VERSION 5.7 ;
  NOWIREEXTENSIONATPIN ON ;
  DIVIDERCHAR "/" ;
  BUSBITCHARS "[]" ;
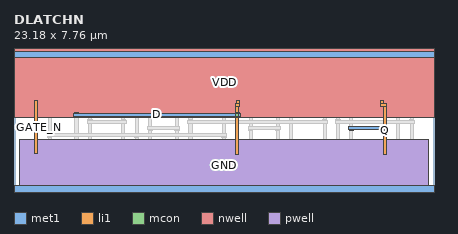
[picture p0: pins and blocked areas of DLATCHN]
MACRO DLATCHN
  CLASS CORE ;
  FOREIGN DLATCHN ;
  ORIGIN 0.000 0.000 ;
  SIZE 23.180 BY 7.760 ;
  SYMMETRY X Y ;
  SITE unitrh ;
  PIN Q
    DIRECTION OUTPUT ;
    USE SIGNAL ;
    ANTENNAGATEAREA 1.027250 ;
    ANTENNADIFFAREA 0.963050 ;
    PORT
      LAYER met1 ;
        RECT 18.505 3.595 18.735 3.625 ;
        RECT 20.355 3.595 20.585 3.625 ;
        RECT 18.475 3.425 20.615 3.595 ;
        RECT 18.505 3.395 18.735 3.425 ;
        RECT 20.355 3.395 20.585 3.425 ;
    END
    PORT
      LAYER li1 ;
        RECT 20.230 4.890 20.400 5.050 ;
        RECT 20.230 4.720 20.555 4.890 ;
        RECT 20.385 2.095 20.555 4.720 ;
      LAYER mcon ;
        RECT 20.385 3.425 20.555 3.595 ;
    END
  END Q
  PIN D
    DIRECTION INPUT ;
    USE SIGNAL ;
    ANTENNAGATEAREA 2.054500 ;
    PORT
      LAYER met1 ;
        RECT 3.335 4.335 3.565 4.365 ;
        RECT 12.215 4.335 12.445 4.365 ;
        RECT 3.305 4.165 12.475 4.335 ;
        RECT 3.335 4.135 3.565 4.165 ;
        RECT 12.215 4.135 12.445 4.165 ;
    END
    PORT
      LAYER li1 ;
        RECT 12.275 4.890 12.445 5.045 ;
        RECT 12.245 4.715 12.445 4.890 ;
        RECT 12.245 2.095 12.415 4.715 ;
      LAYER mcon ;
        RECT 12.245 4.165 12.415 4.335 ;
    END
  END D
  PIN GATE_N
    DIRECTION INPUT ;
    USE SIGNAL ;
    ANTENNAGATEAREA 1.027250 ;
    PORT
      LAYER li1 ;
        RECT 1.145 2.100 1.315 5.045 ;
    END
  END GATE_N
  PIN VDD
    DIRECTION INOUT ;
    USE POWER ;
    SHAPE ABUTMENT ;
    PORT
      LAYER nwell ;
        RECT 0.000 4.110 23.180 7.940 ;
      LAYER met1 ;
        RECT 0.000 7.410 23.180 7.760 ;
    END
  END VDD
  PIN GND
    DIRECTION INOUT ;
    USE GROUND ;
    SHAPE ABUTMENT ;
    PORT
      LAYER pwell ;
        RECT 0.320 0.000 22.860 2.900 ;
      LAYER met1 ;
        RECT 0.000 0.000 23.180 0.350 ;
    END
  END GND
  OBS
      LAYER li1 ;
        RECT 0.000 7.410 23.180 7.760 ;
        RECT 0.320 4.290 0.660 7.410 ;
        RECT 1.080 5.365 1.250 7.410 ;
        RECT 1.520 4.845 1.690 7.200 ;
        RECT 1.960 5.365 2.130 7.410 ;
        RECT 1.520 4.675 2.055 4.845 ;
        RECT 0.320 0.350 0.660 2.900 ;
        RECT 1.885 2.345 2.055 4.675 ;
        RECT 2.540 4.290 2.880 7.410 ;
        RECT 3.300 5.365 3.470 7.410 ;
        RECT 1.515 2.175 2.055 2.345 ;
        RECT 1.035 0.800 1.205 1.930 ;
        RECT 1.515 1.020 1.685 2.175 ;
        RECT 2.005 0.800 2.175 1.930 ;
        RECT 1.035 0.630 2.175 0.800 ;
        RECT 1.035 0.350 1.205 0.630 ;
        RECT 1.520 0.350 1.690 0.630 ;
        RECT 2.005 0.350 2.175 0.630 ;
        RECT 2.540 0.350 2.880 2.900 ;
        RECT 3.365 2.100 3.535 5.045 ;
        RECT 3.740 4.845 3.910 7.200 ;
        RECT 4.180 5.365 4.350 7.410 ;
        RECT 3.740 4.675 4.275 4.845 ;
        RECT 4.105 2.345 4.275 4.675 ;
        RECT 4.760 4.290 5.100 7.410 ;
        RECT 5.635 5.315 5.805 7.410 ;
        RECT 6.075 5.465 6.245 7.200 ;
        RECT 6.515 5.735 6.685 7.410 ;
        RECT 6.955 5.465 7.125 7.200 ;
        RECT 7.395 5.735 7.565 7.410 ;
        RECT 6.075 5.295 7.605 5.465 ;
        RECT 3.735 2.175 4.275 2.345 ;
        RECT 3.255 0.800 3.425 1.930 ;
        RECT 3.735 1.020 3.905 2.175 ;
        RECT 4.225 0.800 4.395 1.930 ;
        RECT 3.255 0.630 4.395 0.800 ;
        RECT 3.255 0.350 3.425 0.630 ;
        RECT 3.740 0.350 3.910 0.630 ;
        RECT 4.225 0.350 4.395 0.630 ;
        RECT 4.760 0.350 5.100 2.900 ;
        RECT 5.955 2.095 6.125 5.045 ;
        RECT 6.725 4.890 6.895 5.045 ;
        RECT 6.695 4.715 6.895 4.890 ;
        RECT 6.695 2.095 6.865 4.715 ;
        RECT 5.540 1.845 5.710 1.925 ;
        RECT 6.510 1.845 6.680 1.925 ;
        RECT 7.435 1.920 7.605 5.295 ;
        RECT 8.090 4.290 8.430 7.410 ;
        RECT 8.850 5.365 9.020 7.410 ;
        RECT 5.540 1.675 6.680 1.845 ;
        RECT 5.540 0.545 5.710 1.675 ;
        RECT 6.025 0.350 6.195 1.300 ;
        RECT 6.510 0.795 6.680 1.675 ;
        RECT 6.995 1.750 7.605 1.920 ;
        RECT 6.995 1.015 7.165 1.750 ;
        RECT 7.480 0.795 7.650 1.565 ;
        RECT 6.510 0.625 7.650 0.795 ;
        RECT 6.510 0.545 6.680 0.625 ;
        RECT 7.480 0.545 7.650 0.625 ;
        RECT 8.090 0.350 8.430 2.900 ;
        RECT 8.915 2.100 9.085 5.045 ;
        RECT 9.290 4.845 9.460 7.200 ;
        RECT 9.730 5.365 9.900 7.410 ;
        RECT 9.290 4.675 9.825 4.845 ;
        RECT 9.655 2.345 9.825 4.675 ;
        RECT 10.310 4.290 10.650 7.410 ;
        RECT 11.185 5.315 11.355 7.410 ;
        RECT 11.625 5.465 11.795 7.200 ;
        RECT 12.065 5.735 12.235 7.410 ;
        RECT 12.505 5.465 12.675 7.200 ;
        RECT 12.945 5.735 13.115 7.410 ;
        RECT 11.625 5.295 13.155 5.465 ;
        RECT 9.285 2.175 9.825 2.345 ;
        RECT 8.805 0.800 8.975 1.930 ;
        RECT 9.285 1.020 9.455 2.175 ;
        RECT 9.775 0.800 9.945 1.930 ;
        RECT 8.805 0.630 9.945 0.800 ;
        RECT 8.805 0.350 8.975 0.630 ;
        RECT 9.290 0.350 9.460 0.630 ;
        RECT 9.775 0.350 9.945 0.630 ;
        RECT 10.310 0.350 10.650 2.900 ;
        RECT 11.505 2.095 11.675 5.045 ;
        RECT 11.090 1.845 11.260 1.925 ;
        RECT 12.060 1.845 12.230 1.925 ;
        RECT 12.985 1.920 13.155 5.295 ;
        RECT 13.640 4.290 13.980 7.410 ;
        RECT 14.400 5.365 14.570 7.410 ;
        RECT 11.090 1.675 12.230 1.845 ;
        RECT 11.090 0.545 11.260 1.675 ;
        RECT 11.575 0.350 11.745 1.300 ;
        RECT 12.060 0.795 12.230 1.675 ;
        RECT 12.545 1.750 13.155 1.920 ;
        RECT 12.545 1.015 12.715 1.750 ;
        RECT 13.030 0.795 13.200 1.565 ;
        RECT 12.060 0.625 13.200 0.795 ;
        RECT 12.060 0.545 12.230 0.625 ;
        RECT 13.030 0.545 13.200 0.625 ;
        RECT 13.640 0.350 13.980 2.900 ;
        RECT 14.465 2.100 14.635 5.045 ;
        RECT 14.840 4.845 15.010 7.200 ;
        RECT 15.280 5.365 15.450 7.410 ;
        RECT 14.840 4.675 15.375 4.845 ;
        RECT 15.205 2.345 15.375 4.675 ;
        RECT 15.860 4.290 16.200 7.410 ;
        RECT 16.735 5.475 16.905 7.205 ;
        RECT 17.175 5.735 17.345 7.410 ;
        RECT 17.615 7.005 18.665 7.175 ;
        RECT 17.615 5.475 17.785 7.005 ;
        RECT 16.735 5.305 17.785 5.475 ;
        RECT 18.055 5.475 18.225 6.745 ;
        RECT 18.495 5.735 18.665 7.005 ;
        RECT 18.055 5.305 18.705 5.475 ;
        RECT 16.900 4.890 17.070 5.050 ;
        RECT 17.830 4.890 18.000 5.050 ;
        RECT 16.900 4.720 17.225 4.890 ;
        RECT 14.835 2.175 15.375 2.345 ;
        RECT 14.355 0.800 14.525 1.930 ;
        RECT 14.835 1.020 15.005 2.175 ;
        RECT 15.325 0.800 15.495 1.930 ;
        RECT 14.355 0.630 15.495 0.800 ;
        RECT 14.355 0.350 14.525 0.630 ;
        RECT 14.840 0.350 15.010 0.630 ;
        RECT 15.325 0.350 15.495 0.630 ;
        RECT 15.860 0.350 16.200 2.900 ;
        RECT 17.055 2.095 17.225 4.720 ;
        RECT 17.795 4.720 18.000 4.890 ;
        RECT 17.795 2.095 17.965 4.720 ;
        RECT 16.640 0.795 16.810 1.925 ;
        RECT 18.535 1.920 18.705 5.305 ;
        RECT 19.190 4.290 19.530 7.410 ;
        RECT 20.065 5.475 20.235 7.205 ;
        RECT 20.505 5.735 20.675 7.410 ;
        RECT 20.945 7.005 21.995 7.175 ;
        RECT 20.945 5.475 21.115 7.005 ;
        RECT 20.065 5.305 21.115 5.475 ;
        RECT 21.385 5.475 21.555 6.745 ;
        RECT 21.825 5.735 21.995 7.005 ;
        RECT 21.385 5.305 22.035 5.475 ;
        RECT 21.160 4.890 21.330 5.050 ;
        RECT 21.125 4.720 21.330 4.890 ;
        RECT 17.125 1.750 18.705 1.920 ;
        RECT 17.125 1.015 17.295 1.750 ;
        RECT 17.610 0.795 17.780 1.570 ;
        RECT 18.095 1.015 18.265 1.750 ;
        RECT 18.580 0.795 18.750 1.570 ;
        RECT 16.640 0.625 18.750 0.795 ;
        RECT 16.640 0.350 16.810 0.625 ;
        RECT 17.125 0.350 17.295 0.625 ;
        RECT 17.610 0.350 17.780 0.625 ;
        RECT 18.095 0.350 18.265 0.625 ;
        RECT 18.580 0.350 18.750 0.625 ;
        RECT 19.190 0.350 19.530 2.900 ;
        RECT 21.125 2.095 21.295 4.720 ;
        RECT 19.970 0.795 20.140 1.925 ;
        RECT 21.865 1.920 22.035 5.305 ;
        RECT 22.520 4.290 22.860 7.410 ;
        RECT 20.455 1.750 22.035 1.920 ;
        RECT 20.455 1.015 20.625 1.750 ;
        RECT 20.940 0.795 21.110 1.570 ;
        RECT 21.425 1.015 21.595 1.750 ;
        RECT 21.910 0.795 22.080 1.570 ;
        RECT 19.970 0.625 22.080 0.795 ;
        RECT 19.970 0.350 20.140 0.625 ;
        RECT 20.455 0.350 20.625 0.625 ;
        RECT 20.940 0.350 21.110 0.625 ;
        RECT 21.425 0.350 21.595 0.625 ;
        RECT 21.910 0.350 22.080 0.625 ;
        RECT 22.520 0.350 22.860 2.900 ;
        RECT 0.000 0.000 23.180 0.350 ;
      LAYER mcon ;
        RECT 0.775 7.495 0.945 7.665 ;
        RECT 1.145 7.495 1.315 7.665 ;
        RECT 1.515 7.495 1.685 7.665 ;
        RECT 1.885 7.495 2.055 7.665 ;
        RECT 2.255 7.495 2.425 7.665 ;
        RECT 2.995 7.495 3.165 7.665 ;
        RECT 3.365 7.495 3.535 7.665 ;
        RECT 3.735 7.495 3.905 7.665 ;
        RECT 4.105 7.495 4.275 7.665 ;
        RECT 4.475 7.495 4.645 7.665 ;
        RECT 5.215 7.495 5.385 7.665 ;
        RECT 5.585 7.495 5.755 7.665 ;
        RECT 5.955 7.495 6.125 7.665 ;
        RECT 6.325 7.495 6.495 7.665 ;
        RECT 6.695 7.495 6.865 7.665 ;
        RECT 7.065 7.495 7.235 7.665 ;
        RECT 7.435 7.495 7.605 7.665 ;
        RECT 7.805 7.495 7.975 7.665 ;
        RECT 8.545 7.495 8.715 7.665 ;
        RECT 8.915 7.495 9.085 7.665 ;
        RECT 9.285 7.495 9.455 7.665 ;
        RECT 9.655 7.495 9.825 7.665 ;
        RECT 10.025 7.495 10.195 7.665 ;
        RECT 10.765 7.495 10.935 7.665 ;
        RECT 11.135 7.495 11.305 7.665 ;
        RECT 11.505 7.495 11.675 7.665 ;
        RECT 11.875 7.495 12.045 7.665 ;
        RECT 12.245 7.495 12.415 7.665 ;
        RECT 12.615 7.495 12.785 7.665 ;
        RECT 12.985 7.495 13.155 7.665 ;
        RECT 13.355 7.495 13.525 7.665 ;
        RECT 14.095 7.495 14.265 7.665 ;
        RECT 14.465 7.495 14.635 7.665 ;
        RECT 14.835 7.495 15.005 7.665 ;
        RECT 15.205 7.495 15.375 7.665 ;
        RECT 15.575 7.495 15.745 7.665 ;
        RECT 16.315 7.495 16.485 7.665 ;
        RECT 16.685 7.495 16.855 7.665 ;
        RECT 17.055 7.495 17.225 7.665 ;
        RECT 17.425 7.495 17.595 7.665 ;
        RECT 17.795 7.495 17.965 7.665 ;
        RECT 18.165 7.495 18.335 7.665 ;
        RECT 18.535 7.495 18.705 7.665 ;
        RECT 18.905 7.495 19.075 7.665 ;
        RECT 19.645 7.495 19.815 7.665 ;
        RECT 20.015 7.495 20.185 7.665 ;
        RECT 20.385 7.495 20.555 7.665 ;
        RECT 20.755 7.495 20.925 7.665 ;
        RECT 21.125 7.495 21.295 7.665 ;
        RECT 21.495 7.495 21.665 7.665 ;
        RECT 21.865 7.495 22.035 7.665 ;
        RECT 22.235 7.495 22.405 7.665 ;
        RECT 1.885 3.055 2.055 3.225 ;
        RECT 3.365 4.165 3.535 4.335 ;
        RECT 4.105 3.795 4.275 3.965 ;
        RECT 5.955 3.795 6.125 3.965 ;
        RECT 6.695 3.055 6.865 3.225 ;
        RECT 7.435 3.425 7.605 3.595 ;
        RECT 8.915 3.425 9.085 3.595 ;
        RECT 9.655 3.795 9.825 3.965 ;
        RECT 11.505 3.055 11.675 3.225 ;
        RECT 12.985 3.425 13.155 3.595 ;
        RECT 14.465 3.425 14.635 3.595 ;
        RECT 15.205 4.165 15.375 4.335 ;
        RECT 17.055 3.795 17.225 3.965 ;
        RECT 17.795 3.795 17.965 3.965 ;
        RECT 18.535 3.425 18.705 3.595 ;
        RECT 21.125 4.165 21.295 4.335 ;
        RECT 21.865 3.795 22.035 3.965 ;
        RECT 0.775 0.095 0.945 0.265 ;
        RECT 1.145 0.095 1.315 0.265 ;
        RECT 1.515 0.095 1.685 0.265 ;
        RECT 1.885 0.095 2.055 0.265 ;
        RECT 2.255 0.095 2.425 0.265 ;
        RECT 2.995 0.095 3.165 0.265 ;
        RECT 3.365 0.095 3.535 0.265 ;
        RECT 3.735 0.095 3.905 0.265 ;
        RECT 4.105 0.095 4.275 0.265 ;
        RECT 4.475 0.095 4.645 0.265 ;
        RECT 5.215 0.095 5.385 0.265 ;
        RECT 5.585 0.095 5.755 0.265 ;
        RECT 5.955 0.095 6.125 0.265 ;
        RECT 6.325 0.095 6.495 0.265 ;
        RECT 6.695 0.095 6.865 0.265 ;
        RECT 7.065 0.095 7.235 0.265 ;
        RECT 7.435 0.095 7.605 0.265 ;
        RECT 7.805 0.095 7.975 0.265 ;
        RECT 8.545 0.095 8.715 0.265 ;
        RECT 8.915 0.095 9.085 0.265 ;
        RECT 9.285 0.095 9.455 0.265 ;
        RECT 9.655 0.095 9.825 0.265 ;
        RECT 10.025 0.095 10.195 0.265 ;
        RECT 10.765 0.095 10.935 0.265 ;
        RECT 11.135 0.095 11.305 0.265 ;
        RECT 11.505 0.095 11.675 0.265 ;
        RECT 11.875 0.095 12.045 0.265 ;
        RECT 12.245 0.095 12.415 0.265 ;
        RECT 12.615 0.095 12.785 0.265 ;
        RECT 12.985 0.095 13.155 0.265 ;
        RECT 13.355 0.095 13.525 0.265 ;
        RECT 14.095 0.095 14.265 0.265 ;
        RECT 14.465 0.095 14.635 0.265 ;
        RECT 14.835 0.095 15.005 0.265 ;
        RECT 15.205 0.095 15.375 0.265 ;
        RECT 15.575 0.095 15.745 0.265 ;
        RECT 16.315 0.095 16.485 0.265 ;
        RECT 16.685 0.095 16.855 0.265 ;
        RECT 17.055 0.095 17.225 0.265 ;
        RECT 17.425 0.095 17.595 0.265 ;
        RECT 17.795 0.095 17.965 0.265 ;
        RECT 18.165 0.095 18.335 0.265 ;
        RECT 18.535 0.095 18.705 0.265 ;
        RECT 18.905 0.095 19.075 0.265 ;
        RECT 19.645 0.095 19.815 0.265 ;
        RECT 20.015 0.095 20.185 0.265 ;
        RECT 20.385 0.095 20.555 0.265 ;
        RECT 20.755 0.095 20.925 0.265 ;
        RECT 21.125 0.095 21.295 0.265 ;
        RECT 21.495 0.095 21.665 0.265 ;
        RECT 21.865 0.095 22.035 0.265 ;
        RECT 22.235 0.095 22.405 0.265 ;
      LAYER met1 ;
        RECT 15.175 4.335 15.405 4.365 ;
        RECT 21.095 4.335 21.325 4.365 ;
        RECT 15.145 4.165 21.355 4.335 ;
        RECT 15.175 4.135 15.405 4.165 ;
        RECT 21.095 4.135 21.325 4.165 ;
        RECT 4.075 3.965 4.305 3.995 ;
        RECT 5.925 3.965 6.155 3.995 ;
        RECT 9.625 3.965 9.855 3.995 ;
        RECT 17.025 3.965 17.255 3.995 ;
        RECT 17.765 3.965 17.995 3.995 ;
        RECT 21.835 3.965 22.065 3.995 ;
        RECT 4.045 3.795 6.185 3.965 ;
        RECT 9.595 3.795 17.285 3.965 ;
        RECT 17.735 3.795 22.095 3.965 ;
        RECT 4.075 3.765 4.305 3.795 ;
        RECT 5.925 3.765 6.155 3.795 ;
        RECT 9.625 3.765 9.855 3.795 ;
        RECT 17.025 3.765 17.255 3.795 ;
        RECT 17.765 3.765 17.995 3.795 ;
        RECT 21.835 3.765 22.065 3.795 ;
        RECT 7.405 3.595 7.635 3.625 ;
        RECT 8.885 3.595 9.115 3.625 ;
        RECT 12.955 3.595 13.185 3.625 ;
        RECT 14.435 3.595 14.665 3.625 ;
        RECT 7.375 3.425 9.145 3.595 ;
        RECT 12.925 3.425 14.695 3.595 ;
        RECT 7.405 3.395 7.635 3.425 ;
        RECT 8.885 3.395 9.115 3.425 ;
        RECT 12.955 3.395 13.185 3.425 ;
        RECT 14.435 3.395 14.665 3.425 ;
        RECT 1.855 3.225 2.085 3.255 ;
        RECT 6.665 3.225 6.895 3.255 ;
        RECT 11.475 3.225 11.705 3.255 ;
        RECT 1.825 3.055 11.735 3.225 ;
        RECT 1.855 3.025 2.085 3.055 ;
        RECT 6.665 3.025 6.895 3.055 ;
        RECT 11.475 3.025 11.705 3.055 ;
  END
END DLATCHN
END LIBRARY

